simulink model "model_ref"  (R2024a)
settings: Solver=ode4  StartTime=0.0  StopTime=10  FixedStep=0.0001  RelTol=1e-3
model workspace (MAT data in the model file):
  Brake_MC_D = 3.3
  CarSimTCKMAP = [0.006425 0.006425 0.006425 0.006425 0.006424 0.006419 0.006386 0.006243 0.005735 0.004185 0.002578 0.000614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]
  CarSimTCLambdaPMAP = [1.864 1.78 1.701 1.608 1.56 1.519 1.464 1.412 1.356 1.309 1.259 1.203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]
  CarSimTCiMAP1 = [0 0.1 0.2 0.3 0.4 0.5 0.6 0.7 0.8 0.9 0.95 0.99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]
  CarSimTCiMAP2 = [0 0.102 0.202 0.306 0.353 0.4 0.452 0.502 0.551 0.6 0.65 0.7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]
  DOWN_Data_lookup = [0 0 0 0 0 0 0 0 0 0 0 0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]
  DOWN_Gear_lookup = [1 2 3 4 5]
  DOWN_Throttle_lookup = [0 1 2 3 4 5 6 7 8 9 10 11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]
  Diff_gear_ratio = 4.1
  MC_lever_ratio = 0.02381
  UP_Data_lookup = [13.2140963951 13.2140963951 13.2140963951 13.2140963951 13.2140963951 13.2140963951 13.6741047457 14.0455395451 14.3574336302 14.6810803701 15.0507893957 16.3806466373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]
  UP_Gear_lookup = [1 2 3 4 5]
  UP_Throttle_lookup = [0 1 2 3 4 5 6 7 8 9 10 11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]
  eng_One_Order_T = 0.005
  eng_T = [0 0 0 0 0 0 0 0 0 0 15 64.064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]
  eng_Ted = 0.005
  eng_n = [0 86.6667 173.333 433.333 750 866.667 1300 1733.33 2166.67 2600 3033.33 3466.67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]
  eng_throttle = [0 0.1 0.15 0.2 0.35 0.5 0.7 0.85 0.95 1]
  rotational_inertia_of_crankshaft = 0.16
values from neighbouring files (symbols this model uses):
  v0 = 0    [init.m]    (also in tempScript.m = 3)
  x0 = -27.92254    [init.m]    (also in tempScript.m = 66.5)
  y0 = 292.5054    [init.m]    (also in tempScript.m = 257.9)
  yaw = 0    [init.m]    (also in tempScript.m = -1.125)
undefined symbols (not defined in the file or in its folder): a_brake, a_thr, brake_table, thr_table
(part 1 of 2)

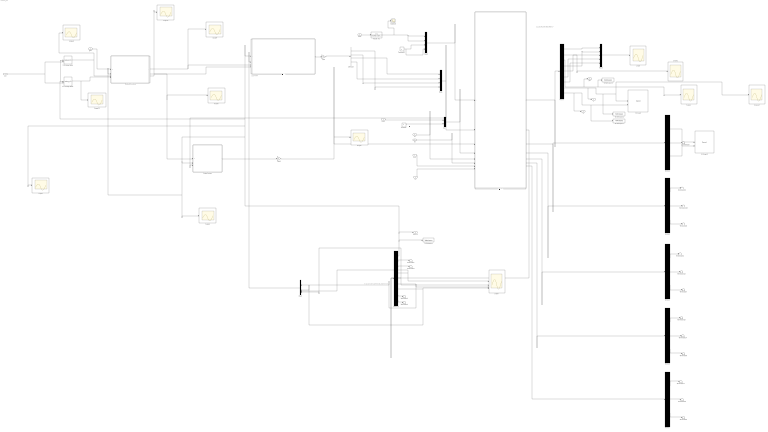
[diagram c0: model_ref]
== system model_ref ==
  note: 前轮
  note: 路肩
  note: x y phi AFL AFR ARL ARR X Y
  note: 档位 D N R P
  note: dx dy dphi dAFL dAFR dARL dARR dX dY
  note: 后轮
  note: 坡度
  acc : Inport  OutDataTypeStr=double  PortDimensions=1
  gear : Inport  Port=2  OutDataTypeStr=double  PortDimensions=1
  steer : Inport  Port=3  OutDataTypeStr=double  PortDimensions=1
  slope : Inport  Port=4  OutDataTypeStr=double  PortDimensions=1
  x0 : Inport  Port=5  OutDataTypeStr=double  PortDimensions=1
  y0 : Inport  Port=6  OutDataTypeStr=double  PortDimensions=1
  yaw : Inport  Port=7  OutDataTypeStr=double  PortDimensions=1
  v0 : Inport  Port=8  OutDataTypeStr=double  PortDimensions=1
  2-D Lookup Table : Lookup_n-D  BreakpointsForDimension1=0:0.1:12  BreakpointsForDimension2=a_thr  Table=thr_table  InternalRulePriority=Speed  RndMeth=Simplest
  2-D Lookup Table1 : Lookup_n-D  BreakpointsForDimension1=0:0.1:12  BreakpointsForDimension2=a_brake  Table=brake_table  InternalRulePriority=Speed  RndMeth=Simplest
  Brake System : Subsystem
  Constant : Constant  Value=0
  Constant11 : Constant  Value=0
  Demux : Demux  Outputs=[1 1 1 1 1 1 1 1 1]
  Demux1 : Demux  Outputs=[1 1 1 1 1 1 1 1 1]
  Demux2 : Demux  Outputs=[1 1 1 1]
  Demux{3..7} (5 alike) : Demux  Outputs=[1 1 1]
  Gain : Gain  Gain=1/5
  Gain1 : Gain
  MATLAB Function1 : MATLAB Function  TreatAsAtomicUnit=on
  Mux : Mux  Inputs=[1 1]
  Mux1 : Mux  Inputs=[1 1 1 1]
  Mux3 : Mux  Inputs=[1 1 1 1]
  Mux4 : Mux  Inputs=5
  Mux5 : Mux
  Scope{,1..6,8..13} (13 alike) : Scope
  Scope7 : Scope  NumInputPorts=4
  Terminator{1..17} (17 alike) : Terminator
  To Workspace : ToWorkspace  VariableName=velocity1  SaveFormat=Timeseries  SampleTime=-1
  To Workspace1 : ToWorkspace  VariableName=phi1  SaveFormat=Timeseries  SampleTime=-1
  To Workspace2 : ToWorkspace  VariableName=x1  SaveFormat=Timeseries  SampleTime=-1
  To Workspace3 : ToWorkspace  VariableName=y1  SaveFormat=Timeseries  SampleTime=-1
  Transfer Fcn : TransferFcn  Denominator=[0.0001 0.01414 1]
  XY Graph : Record  FileSettingsInternal="{\"entries\":[{\"content\":{\"excelSettings\":{\"content\":{},\"type\":\"Streamout.ExcelSettings\"}},\"type\":\"Streamout.FileSettingStorage\",\"uuid\":\"\"}],\"packageUris\":[\"http:\\/\\/schema.mathworks.com\\/mf0\\/streamout_blocks\\/R2020a\"],\"version\":\"1.0\"}"  Layout=[1 1]  SignalsInternal="{\"entries\":[{\"content\":{\"signals\":[{\"content\":{\"blockPath\":[],\"dimensions\":[1],\"domain\":\"\",\"lineColor\":\"#a2142f\",\"plots\":[ 1 ],\"port\":1,\"signalID\":1,\"signalName\":\"Demux:8\"},\"type\":\"RecordBlkView.Signal\",\"uuid\":\"\"},{\"content\":{\"blockPath\":[],\"dimensions\":[1],\"domain\":\"\",\"lineColor\":\"#139fff\",\"plots\":[ 1 ],\"port\":2,\"signalID\":2,\"signalName\":\"Demux:9\"},\"type\":\"RecordBlkView.Signal\",\"uuid\":\"\"}]},\"type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"  VisualizationBindings="{\"xyplotplugin\":{\"info\":[{\"series\":[{\"bindingParametersList\":[{\"parameter\":\"X-Axis\",\"signalID\":1,\"signalName\":\"Demux:8\"},{\"parameter\":\"Y-Axis\",\"signalID\":2,\"signalName\":\"Demux:9\"}],\"seriesID\":0}],\"subplotID\":1}]}}"  CompatibilityTag=XY  st=-1
  XY Graph1 : Record  FileSettingsInternal="{\"entries\":[{\"content\":{\"excelSettings\":{\"content\":{},\"type\":\"Streamout.ExcelSettings\"}},\"type\":\"Streamout.FileSettingStorage\",\"uuid\":\"\"}],\"packageUris\":[\"http:\\/\\/schema.mathworks.com\\/mf0\\/streamout_blocks\\/R2020a\"],\"version\":\"1.0\"}"  Layout=[1 1]  SignalsInternal="{\"entries\":[{\"content\":{\"signals\":[{\"content\":{\"blockPath\":[],\"dimensions\":[1],\"domain\":\"\",\"lineColor\":\"#a2142f\",\"plots\":[ 1 ],\"port\":1,\"signalID\":1,\"signalName\":\"Demux3:1\"},\"type\":\"RecordBlkView.Signal\",\"uuid\":\"\"},{\"content\":{\"blockPath\":[],\"dimensions\":[1],\"domain\":\"\",\"lineColor\":\"#139fff\",\"plots\":[ 1 ],\"port\":2,\"signalID\":2,\"signalName\":\"Demux3:3\"},\"type\":\"RecordBlkView.Signal\",\"uuid\":\"\"}]},\"ty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"  VisualizationBindings="{\"xyplotplugin\":{\"info\":[{\"series\":[{\"bindingParametersList\":[{\"parameter\":\"X-Axis\",\"signalID\":1,\"signalName\":\"Demux3:1\"},{\"parameter\":\"Y-Axis\",\"signalID\":2,\"signalName\":\"Demux3:3\"}],\"seriesID\":0}],\"subplotID\":1}]}}"  CompatibilityTag=XY  st=-1
  车辆动力学模型 : Subsystem
  驱动系统 : Subsystem
  x : Outport  OutDataTypeStr=double  PortDimensions=1  SampleTime=0
  y : Outport  Port=2  OutDataTypeStr=double  PortDimensions=1  SampleTime=0
  phi : Outport  Port=3  OutDataTypeStr=double  PortDimensions=1  SampleTime=0
  velocity : Outport  Port=4  OutDataTypeStr=double  PortDimensions=1  SampleTime=0
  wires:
  Demux2/2 -> Mux1/3
  车辆动力学模型/1(车辆位移状态) -> Demux/1
  Demux/6 -> Mux4/4
  Constant11/1 -> Mux3/4, Mux3/3
  Constant/1 -> Mux/2
  车辆动力学模型/2(车辆速度状态) -> Demux1/1
  acc/1 -> 2-D Lookup Table1/2, 2-D Lookup Table/2
  Demux1/3 -> Terminator2/1
  Demux1/2 -> Terminator1/1
  Demux6/2 -> Terminator14/1
  Mux5/1 -> 驱动系统/2(" 车轮角速度")
  MATLAB Function1/1(Dr_C) -> Scope4/1, 驱动系统/3(" 节气门开度")
  Demux7/1 -> Terminator17/1
  slope/1 -> Mux/1
  Demux6/1 -> Terminator15/1
  Mux3/1 -> 车辆动力学模型/1(Steering)
  MATLAB Function1/2(Br_C) -> Brake System/1(BrkPdlCmd), Scope5/1
  Demux/1 -> Mux4/1
  车辆动力学模型/4(全局坐标系_FL) -> Demux4/1
  Demux6/3 -> Terminator8/1
  steer/1 -> Transfer Fcn/1
  Demux1/6 -> Mux5/1, Scope7/3
  Demux7/2 -> Terminator16/1
  Demux/4 -> Mux4/2
  Brake System/1(BrkTrq) -> Gain1/1
  Demux3/3 -> XY Graph1/2
  车辆动力学模型/3(全局坐标系_质心) -> Demux3/1
  Demux2/1 -> Mux1/4
  Demux5/2 -> Terminator12/1
  Demux2/3 -> Mux1/1
  2-D Lookup Table1/1 -> Scope13/1, MATLAB Function1/4(bra)
  Demux7/3 -> Terminator9/1
  Demux/5 -> Mux4/3
  车辆动力学模型/7(全局坐标系_RR) -> Demux7/1
  Demux4/1 -> Terminator11/1
  Demux1/9 -> Terminator4/1
  Mux4/1 -> Scope/1
  Demux1/1 -> velocity/1, MATLAB Function1/2(v_x), Scope9/1, Brake System/2(dx), Scope3/1, 驱动系统/1(Vel_x 车辆纵向速度), 2-D Lookup Table1/1, 2-D Lookup Table/1, To Workspace/1
  Demux3/1 -> XY Graph1/1
  Gain1/1 -> 车辆动力学模型/3(Tor_B), Scope6/1
  2-D Lookup Table/1 -> MATLAB Function1/3(thrs), Scope8/1
  Demux1/4 -> Mux5/3, Scope7/1
  Demux4/3 -> Terminator6/1
  Demux1/5 -> Mux5/4, Scope7/2
  Demux2/4 -> Mux1/2
  Gain/1 -> Demux2/1
  MATLAB Function1/3(gear) -> Scope11/1, 驱动系统/4(档_D_N_R_P)
  Demux1/8 -> Terminator3/1
  Demux5/1 -> Terminator13/1
  Demux/9 -> y/1, To Workspace3/1, XY Graph/2
  Demux5/3 -> Terminator7/1
  Demux/2 -> Scope1/1
  Mux1/1 -> 车辆动力学模型/2(Tor_D), Brake System/3(怠速力矩)
  驱动系统/1(" 车轮输入力矩") -> Gain/1
  车辆动力学模型/6(全局坐标系_RL) -> Demux6/1
  gear/1 -> MATLAB Function1/1("gear ")
  Transfer Fcn/1 -> Scope10/1, Mux3/2, Mux3/1
  Demux3/2 -> Terminator5/1
  Demux1/7 -> Mux5/2, Scope7/4
  Demux4/2 -> Terminator10/1
  车辆动力学模型/5(全局坐标系_FR) -> Demux5/1
  Demux/3 -> phi/1, To Workspace1/1, Scope2/1
  Demux/8 -> x/1, To Workspace2/1, Scope12/1, XY Graph/1
  Demux/7 -> Mux4/5
  Mux/1 -> 车辆动力学模型/4(road)
  x0/1 -> 车辆动力学模型/5(x0)
  y0/1 -> 车辆动力学模型/6(y0)
  yaw/1 -> 车辆动力学模型/7(yaw)
  v0/1 -> 车辆动力学模型/8(v0)

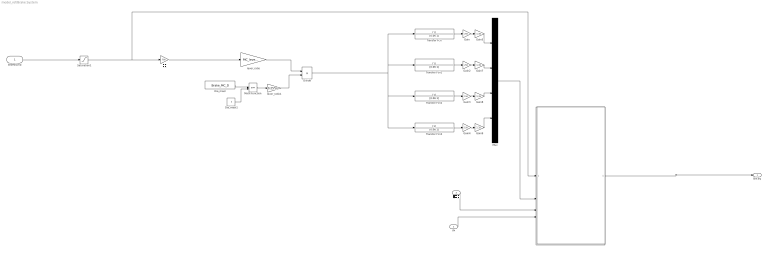
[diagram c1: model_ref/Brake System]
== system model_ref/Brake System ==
  BrkPdlCmd : Inport
  dx : Inport  Port=2
  怠速力矩 : Inport  Port=3
  Dia_mast : Constant  Value=Brake_MC_D
  Dia_mast1 : Constant  Value=2
  Divide : Product  Inputs=*/
  Gain : Gain  Gain=250
  Gain2 : Gain  Gain=250
  Gain3 : Gain  Gain=150
  Gain4 : Gain  Gain=150
  Gain{5,7..9} (4 alike) : Gain  Gain=1.35
  Math Function : Math  Operator=pow  SignedPower=on
  Mux : Mux  Inputs=[1 1 1 1]
  Saturation1 : Saturate  UpperLimit=1  LowerLimit=0
  Transfer Fcn{,1..3} (4 alike) : TransferFcn  Denominator=[0.06 1]
  lever_ratio : Gain  Gain=MC_lever_ratio
  lever_ratio1 : Gain  Gain=0.25*pi
  制动转矩 : MATLAB Function  TreatAsAtomicUnit=on
  行程 : Gain  Gain=700
  BrkTrq : Outport
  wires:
  Gain/1 -> Gain5/1
  Gain4/1 -> Gain9/1
  Gain2/1 -> Gain7/1
  Gain3/1 -> Gain8/1
  Transfer Fcn3/1 -> Gain4/1
  Transfer Fcn2/1 -> Gain3/1
  Transfer Fcn1/1 -> Gain2/1
  BrkPdlCmd/1 -> Saturation1/1
  Transfer Fcn/1 -> Gain/1
  Dia_mast1/1 -> Math Function/2
  lever_ratio1/1 -> Divide/2
  Dia_mast/1 -> Math Function/1
  Math Function/1 -> lever_ratio1/1
  lever_ratio/1 -> Divide/1
  Gain5/1 -> Mux/1
  Gain7/1 -> Mux/2
  Gain8/1 -> Mux/3
  Gain9/1 -> Mux/4
  行程/1 -> lever_ratio/1
  Divide/1 -> Transfer Fcn/1, Transfer Fcn1/1, Transfer Fcn3/1, Transfer Fcn2/1
  制动转矩/1(y) -> BrkTrq/1
  dx/1 -> 制动转矩/4(dx)
  Mux/1 -> 制动转矩/2(Tor_Br)
  怠速力矩/1 -> 制动转矩/3(Tor_Dr)
  Saturation1/1 -> 制动转矩/1(Br_Con), 行程/1

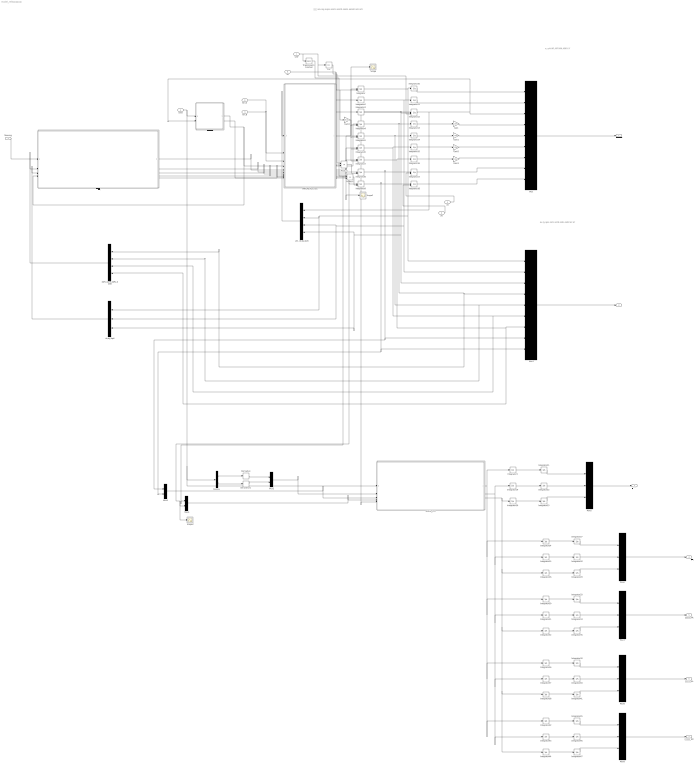
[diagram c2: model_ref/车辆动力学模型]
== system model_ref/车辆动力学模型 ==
  note: x y phi AFL AFR ARL ARR X Y
  note: dx dy dphi dAFL dAFR dARL dARR dX dY
  note: 输出： ddx ddy ddphi ddAFL ddAFR ddARL ddARR ddX ddY
  Steering : Inport
  Tor_D : Inport  Port=2
  Tor_B : Inport  Port=3
  road : Inport  Port=4
  x0 : Inport  Port=5
  y0 : Inport  Port=6
  yaw : Inport  Port=7
  v0 : Inport  Port=8
  Cos : Trigonometry  Operator=cos
  Demux : Demux  Outputs=[1 1]
  Derivative : Derivative
  Derivative1 : Derivative
  Gain{,1..3} (4 alike) : Gain  Gain=0.314
  Gain4 : Gain  Gain=1/0.314
  Global_XYZ : MATLAB Function  TreatAsAtomicUnit=on
  Integrator : Integrator  InitialConditionSource=external  InitialCondition=v0
  Integrator{1..3,10..11,13..16,19..47} (38 alike) : Integrator
  Integrator12 : Integrator  InitialConditionSource=external  InitialCondition=yaw
  Integrator17 : Integrator  InitialConditionSource=external  InitialCondition=x0
  Integrator18 : Integrator  InitialConditionSource=external  InitialCondition=y0
  Integrator{4..7} (4 alike) : Integrator  InitialConditionSource=external  InitialCondition=v0/0.314
  Integrator8 : Integrator  InitialConditionSource=external  InitialCondition=v0*cos(yaw)
  Integrator9 : Integrator  InitialConditionSource=external  InitialCondition=v0*sin(yaw)
  MATLAB Function : MATLAB Function  TreatAsAtomicUnit=on
  Mux : Mux  Inputs=[1 1 1 1 1 1 1 1 1]
  Mux1 : Mux  Inputs=[1 1 1 1 1 1 1 1 1]
  Mux2 : Mux  Inputs=[1 1]
  Mux3 : Mux  Inputs=[1 1]
  Mux4 : Mux  Inputs=[1 1]
  Mux{5..9} (5 alike) : Mux  Inputs=[1 1 1]
  Product : Product
  Product1 : Product
  Scope : Scope
  Scope1 : Scope
  Scope2 : Scope
  Trigonometric Function : Trigonometry
  dAFL,dAFR,dARL,dARR : Mux  Inputs=[1 1 1 1]
  dx,dy,dphi : Mux  Inputs=[1 1 1]
  "phi, dx,dy,dphi" : Mux  Inputs=[1 1 1 1]
  车轮系统 : Subsystem
  轮胎垂直载荷 : Subsystem
  车辆位移状态 : Outport
  车辆速度状态 : Outport  Port=2
  全局坐标系_质心 : Outport  Port=3
  全局坐标系_FL : Outport  Port=4
  全局坐标系_FR : Outport  Port=5
  全局坐标系_RL : Outport  Port=6
  全局坐标系_RR : Outport  Port=7
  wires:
  Product/1 -> Integrator8/2
  Global_XYZ/1(ddX_G) -> Integrator24/1, Integrator30/1, Integrator36/1, Integrator42/1, Integrator1/1
  yaw/1 -> Trigonometric Function/1, Cos/1, Integrator12/2
  Integrator40/1 -> Mux8/2
  Gain3/1 -> Mux/7
  Mux1/1 -> 车辆速度状态/1
  Integrator47/1 -> Mux9/3
  Integrator38/1 -> Integrator41/1
  轮胎垂直载荷/2(w_cg) -> MATLAB Function/10(w_cg)
  road/1 -> 轮胎垂直载荷/1(road), Global_XYZ/1(road), Demux/1
  Integrator46/1 -> Mux9/2
  Gain1/1 -> Mux/5
  Integrator14/1 -> Gain1/1
  Mux4/1 -> Global_XYZ/4(ddu)
  Trigonometric Function/1 -> Product1/1
  Integrator16/1 -> Gain3/1
  车轮系统/3(左后轮胎力) -> MATLAB Function/7(FwRL)
  MATLAB Function/8(ddX) -> Scope1/1, Integrator8/1, Mux4/1
  Integrator26/1 -> Integrator29/1
  MATLAB Function/5(ddAFR) -> Integrator5/1
  Integrator24/1 -> Integrator27/1
  Product1/1 -> Integrator9/2
  Integrator11/1 -> Mux/2
  Integrator19/1 -> Integrator22/1
  Integrator32/1 -> Integrator35/1
  y0/1 -> Integrator18/2
  v0/1 -> Product1/2, Product/2, Gain4/1, Integrator/2
  Mux9/1 -> 全局坐标系_RR/1
  Derivative/1 -> Mux2/1
  Integrator29/1 -> Mux6/3
  "phi, dx,dy,dphi"/1 -> MATLAB Function/1(u)
  Integrator7/1 -> Integrator16/1, Mux1/7, dAFL,dAFR,dARL,dARR/4
  Mux6/1 -> 全局坐标系_FL/1
  Integrator2/1 -> Integrator11/1, Mux1/2, "phi, dx,dy,dphi"/3, dx,dy,dphi/2
  dx,dy,dphi/1 -> 车轮系统/3(纵向速度 横向速度 横摆角速度)
  Integrator25/1 -> Integrator28/1
  Integrator27/1 -> Mux6/1
  Cos/1 -> Product/1
  车轮系统/2(右前轮胎力) -> MATLAB Function/6(FwFR)
  Integrator/1 -> Integrator10/1, Mux1/1, "phi, dx,dy,dphi"/2, dx,dy,dphi/1
  Integrator15/1 -> Gain2/1
  车轮系统/5(四轮转向角) -> MATLAB Function/9(Steering)
  Integrator1/1 -> Integrator21/1
  MATLAB Function/6(ddARL) -> Integrator6/1
  Tor_D/1 -> MATLAB Function/2(Tor_D)
  Gain2/1 -> Mux/6
  Integrator45/1 -> Mux9/1
  轮胎垂直载荷/1(Fz) -> MATLAB Function/4(Fz), 车轮系统/4(轮胎垂直载荷)
  Integrator20/1 -> Integrator23/1
  车轮系统/1(左前轮胎力) -> MATLAB Function/5(FwFL)
  Integrator6/1 -> Integrator15/1, Mux1/6, dAFL,dAFR,dARL,dARR/3
  Integrator33/1 -> Mux7/1
  Integrator31/1 -> Integrator34/1
  x0/1 -> Integrator17/2
  Integrator44/1 -> Integrator47/1
  Integrator3/1 -> Integrator12/1, Mux1/3, "phi, dx,dy,dphi"/4, dx,dy,dphi/3
  Mux5/1 -> 全局坐标系_质心/1
  Integrator42/1 -> Integrator45/1
  Mux8/1 -> 全局坐标系_RL/1
  Mux2/1 -> Global_XYZ/2(droad)
  Integrator21/1 -> Mux5/1
  Integrator18/1 -> Mux/9
  Integrator43/1 -> Integrator46/1
  MATLAB Function/9(ddY) -> Mux4/2, Scope2/1, Integrator9/1
  Integrator9/1 -> Integrator18/1, Mux3/2, Mux1/9
  Integrator13/1 -> Gain/1
  Integrator28/1 -> Mux6/2
  车轮系统/4(右后轮胎力) -> MATLAB Function/8(FwRR)
  Integrator35/1 -> Mux7/3
  MATLAB Function/2(ddy) -> Integrator2/1
  MATLAB Function/3(ddphi) -> Integrator3/1
  Mux3/1 -> Global_XYZ/3(du)
  Derivative1/1 -> Mux2/2
  Demux/2 -> Derivative1/1
  Integrator4/1 -> Integrator13/1, Mux1/4, dAFL,dAFR,dARL,dARR/1
  Integrator23/1 -> Mux5/3
  Global_XYZ/3(ddZ_G) -> Integrator26/1, Integrator32/1, Integrator38/1, Integrator44/1, Integrator20/1
  Integrator22/1 -> Mux5/2
  MATLAB Function/1(ddx) -> Scope/1, Integrator/1
  Integrator5/1 -> Integrator14/1, dAFL,dAFR,dARL,dARR/2, Mux1/5
  Integrator36/1 -> Integrator39/1
  Gain/1 -> Mux/4
  Tor_B/1 -> MATLAB Function/3(Tor_B)
  Global_XYZ/2(ddY_G) -> Integrator25/1, Integrator31/1, Integrator37/1, Integrator43/1, Integrator19/1
  Integrator17/1 -> Mux/8
  Mux7/1 -> 全局坐标系_FR/1
  Steering/1 -> 车轮系统/1(转向角)
  Integrator37/1 -> Integrator40/1
  MATLAB Function/4(ddAFL) -> Integrator4/1
  Gain4/1 -> Integrator7/2, Integrator6/2, Integrator5/2, Integrator4/2
  Integrator8/1 -> Integrator17/1, Mux3/1, Mux1/8
  Integrator41/1 -> Mux8/3
  Integrator12/1 -> Global_XYZ/5(phi), "phi, dx,dy,dphi"/1, Mux/3, 轮胎垂直载荷/2(横摆角)
  Integrator30/1 -> Integrator33/1
  dAFL,dAFR,dARL,dARR/1 -> 车轮系统/2(轮胎角速度)
  Integrator10/1 -> Mux/1
  Integrator39/1 -> Mux8/1
  Demux/1 -> Derivative/1
  Integrator34/1 -> Mux7/2
  MATLAB Function/7(ddARR) -> Integrator7/1
  Mux/1 -> 车辆位移状态/1

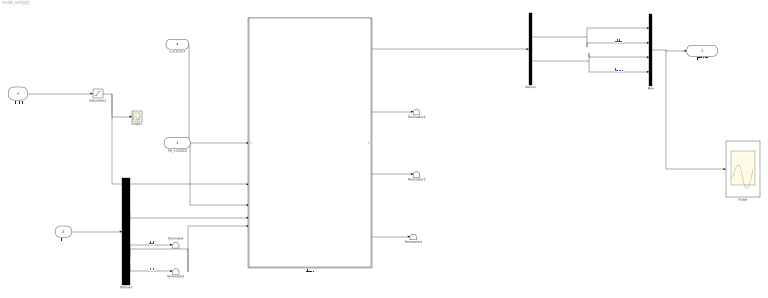
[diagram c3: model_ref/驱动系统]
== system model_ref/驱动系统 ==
  Vel_x 车辆纵向速度 : Inport
  " 车轮角速度" : Inport  Port=2
  " 节气门开度" : Inport  Port=3
  档_D_N_R_P : Inport  Port=4
  Demux : Demux  Outputs=2
  Demux1 : Demux
  Mux : Mux  Inputs=[1 1 1 1]
  Saturation1 : Saturate  UpperLimit=1  LowerLimit=0
  Scope : Scope
  Scope1 : Scope
  Terminator{,1..4} (5 alike) : Terminator
  发动机模型 : Subsystem
  " 车轮输入力矩" : Outport
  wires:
  " 节气门开度"/1 -> Saturation1/1
  发动机模型/3(Gear) -> Terminator3/1
  Vel_x 车辆纵向速度/1 -> 发动机模型/3(Vel_x 车辆纵向速度)
  发动机模型/4(TCRatio) -> Terminator4/1
  发动机模型/2(EngSpd) -> Terminator2/1
  Saturation1/1 -> Scope1/1, 发动机模型/2(节气门开度)
  发动机模型/1(WhlTrq) -> Demux/1
  档_D_N_R_P/1 -> 发动机模型/1(GearCmd)
  Mux/1 -> Scope/1, " 车轮输入力矩"/1
  Demux/2 -> Mux/4, Mux/3  "从动轮力矩"
  Demux/1 -> Mux/2, Mux/1  "驱动轮力矩"
  Demux1/1 -> 发动机模型/4(驱动轮_L)
  Demux1/2 -> 发动机模型/5(驱动轮_R)
  Demux1/4 -> Terminator1/1  "从动轮"
  Demux1/3 -> Terminator/1  "从动轮"
  " 车轮角速度"/1 -> Demux1/1

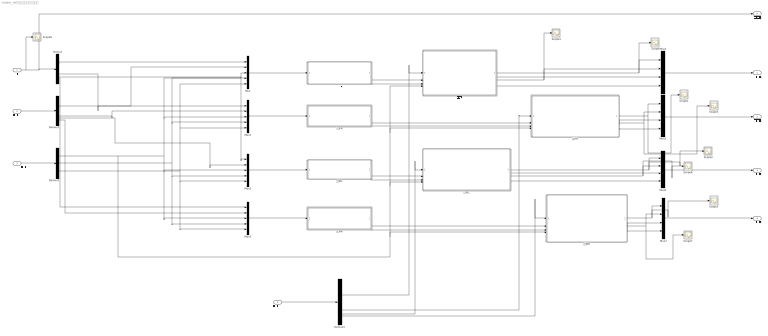
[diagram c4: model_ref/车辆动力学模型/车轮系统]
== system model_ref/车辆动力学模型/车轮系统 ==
  转向角 : Inport
  轮胎角速度 : Inport  Port=2
  纵向速度 横向速度 横摆角速度 : Inport  Port=3
  轮胎垂直载荷 : Inport  Port=4
  Demux : Demux
  Demux1 : Demux
  Demux2 : Demux  Outputs=3
  Demux3 : Demux
  Mux{,1..3} (4 alike) : Mux  Inputs=[1 1 1 1 1]
  Mux{4..7} (4 alike) : Mux  Inputs=[1 1 1 1]
  Scope{,1..8} (9 alike) : Scope
  车轮FL : MATLAB Function  TreatAsAtomicUnit=on
  车轮FR : MATLAB Function  TreatAsAtomicUnit=on
  车轮RL : MATLAB Function  TreatAsAtomicUnit=on
  车轮RR : MATLAB Function  TreatAsAtomicUnit=on
  轮胎FL : MATLAB Function  TreatAsAtomicUnit=on
  轮胎FR : MATLAB Function  TreatAsAtomicUnit=on
  轮胎RL : MATLAB Function  TreatAsAtomicUnit=on
  轮胎RR : MATLAB Function  TreatAsAtomicUnit=on
  左前轮胎力 : Outport
  右前轮胎力 : Outport  Port=2
  左后轮胎力 : Outport  Port=3
  右后轮胎力 : Outport  Port=4
  四轮转向角 : Outport  Port=5
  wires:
  Mux7/1 -> 右后轮胎力/1
  Demux2/1 -> Mux1/3, Mux/3, Mux3/3, Mux2/3, 轮胎RR/4(VS), 轮胎FR/4(VS), 轮胎FL/4(VS), 轮胎RL/4(VS)
  Mux6/1 -> 左后轮胎力/1
  Mux5/1 -> 右前轮胎力/1
  Mux4/1 -> 左前轮胎力/1
  轮胎FL/3(MZ0) -> Mux4/3
  轮胎RR/4(MY) -> Mux7/4
  轮胎RR/3(MZ0) -> Mux7/3
  轮胎RR/2(FY0) -> Mux7/2, Scope7/1
  轮胎RR/1(FX0) -> Mux7/1, Scope3/1
  轮胎RL/4(MY) -> Mux6/4
  轮胎RL/3(MZ0) -> Mux6/3
  轮胎RL/2(FY0) -> Mux6/2, Scope6/1
  轮胎RL/1(FX0) -> Mux6/1, Scope2/1
  轮胎FR/4(MY) -> Mux5/4
  轮胎FR/3(MZ0) -> Mux5/3
  轮胎FR/2(FY0) -> Mux5/2, Scope5/1
  轮胎FR/1(FX0) -> Mux5/1, Scope1/1
  轮胎FL/4(MY) -> Mux4/4
  轮胎FL/2(FY0) -> Scope4/1, Mux4/2
  轮胎FL/1(FX0) -> Mux4/1, Scope/1
  Demux3/1 -> 轮胎FL/1(FZ)
  Demux3/2 -> 轮胎FR/1(FZ)
  Demux3/3 -> 轮胎RL/1(FZ)
  Demux3/4 -> 轮胎RR/1(FZ)
  轮胎垂直载荷/1 -> Demux3/1
  车轮RR/1(sigma_x) -> 轮胎RR/2(KAPPA)
  车轮RR/2(alpha) -> 轮胎RR/3(ALPHA)
  车轮RL/2(alpha) -> 轮胎RL/3(ALPHA)
  车轮RL/1(sigma_x) -> 轮胎RL/2(KAPPA)
  车轮FR/1(sigma_x) -> 轮胎FR/2(KAPPA)
  车轮FR/2(alpha) -> 轮胎FR/3(ALPHA)
  车轮FL/2(alpha) -> 轮胎FL/3(ALPHA)
  车轮FL/1(sigma_x) -> 轮胎FL/2(KAPPA)
  Mux1/1 -> 车轮FR/1(u)
  Demux2/3 -> Mux1/5, Mux/5, Mux3/5, Mux2/5
  Demux2/2 -> Mux1/4, Mux/4, Mux3/4, Mux2/4
  Demux1/4 -> Mux3/2
  Demux1/3 -> Mux2/2
  Demux1/2 -> Mux1/2
  Demux1/1 -> Mux/2
  纵向速度 横向速度 横摆角速度/1 -> Demux2/1
  轮胎角速度/1 -> Demux1/1
  Demux/4 -> Mux3/1
  Demux/3 -> Mux2/1
  Demux/2 -> Mux1/1
  Demux/1 -> Mux/1
  转向角/1 -> Scope8/1, Demux/1, 四轮转向角/1
  Mux3/1 -> 车轮RR/1(u)
  Mux2/1 -> 车轮RL/1(u)
  Mux/1 -> 车轮FL/1(u)

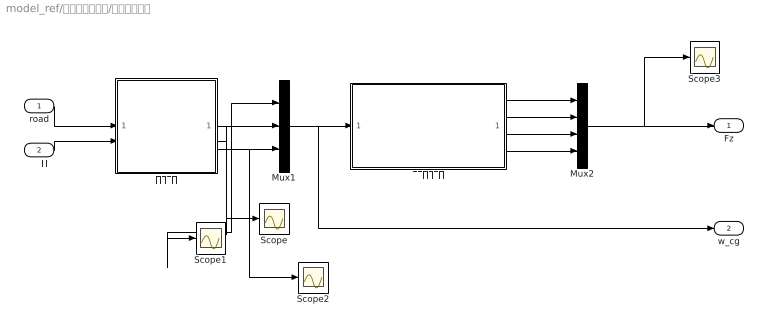
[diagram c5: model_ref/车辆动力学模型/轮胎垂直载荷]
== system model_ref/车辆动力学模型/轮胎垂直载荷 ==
  road : Inport
  横摆角 : Inport  Port=2
  Mux1 : Mux  Inputs=[1 1 1]
  Mux2 : Mux  Inputs=[1 1 1 1]
  Scope{,1..3} (4 alike) : Scope
  车辆重力 : MATLAB Function  TreatAsAtomicUnit=on
  轮胎垂直载荷 : MATLAB Function  TreatAsAtomicUnit=on
  Fz : Outport
  w_cg : Outport  Port=2
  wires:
  横摆角/1 -> 车辆重力/2(phi)
  车辆重力/1(G_x) -> Mux1/1, Scope1/1
  车辆重力/3(G_z) -> Mux1/3, Scope2/1
  Mux1/1 -> 轮胎垂直载荷/1(u), w_cg/1
  轮胎垂直载荷/2(Fz_FR) -> Mux2/2
  Mux2/1 -> Fz/1, Scope3/1
  轮胎垂直载荷/1(Fz_FL) -> Mux2/1
  轮胎垂直载荷/3(Fz_RL) -> Mux2/3
  轮胎垂直载荷/4(Fz_RR) -> Mux2/4
  车辆重力/2(G_y) -> Mux1/2, Scope/1
  road/1 -> 车辆重力/1(u)

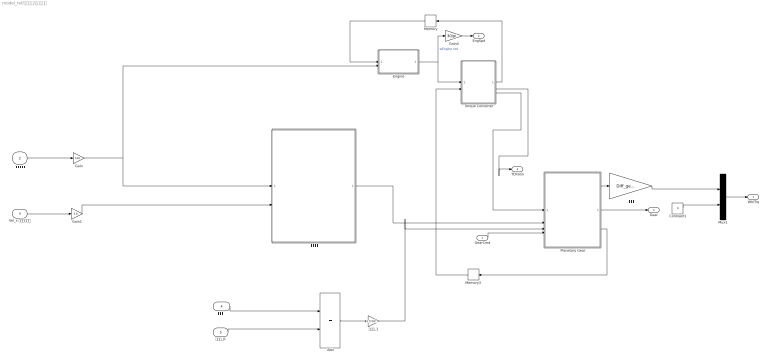
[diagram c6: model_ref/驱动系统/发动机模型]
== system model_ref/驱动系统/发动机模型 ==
  GearCmd : Inport
  节气门开度 : Inport  Port=2
  Vel_x 车辆纵向速度 : Inport  Port=3
  驱动轮_L : Inport  Port=4
  驱动轮_R : Inport  Port=5
  Add : Sum
  Constant1 : Constant  Value=0
  Engine : Subsystem
  Gain : Gain  Gain=100
  Gain1 : Gain  Gain=3.6
  Gain4 : Gain  Gain=30/pi
  Memory : Memory
  Memory3 : Memory
  Mux1 : Mux  Inputs=2
  Planetary Gear : Subsystem
  Torque Converter : Subsystem
  主减速 : Gain  Gain=Diff_gear_ratio/2
  主减速_1 : Gain  Gain=0.5*Diff_gear_ratio
  升降档位 : Subsystem
  WhlTrq : Outport
  EngSpd : Outport  Port=2
  Gear : Outport  Port=3
  TCRatio : Outport  Port=4
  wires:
  Planetary Gear/2(GearOut) -> Gear/1
  升降档位/1(档位) -> Planetary Gear/2(Gear)
  Gain1/1 -> 升降档位/2(Vel_x 车辆纵向速度)
  GearCmd/1 -> Planetary Gear/4(GearCmd)
  Torque Converter/2(TCi) -> TCRatio/1
  Memory3/1 -> Torque Converter/2(wt)
  Gain/1 -> Engine/2(Throttle), 升降档位/1(节气门开度)
  节气门开度/1 -> Gain/1
  Torque Converter/1(Tp) -> Memory/1
  主减速_1/1 -> Planetary Gear/3(whlSpd)
  Gain4/1 -> EngSpd/1
  Planetary Gear/1(To) -> 主减速/1
  Planetary Gear/3(TurboSpd) -> Memory3/1
  Engine/1(发动机输出角速度) -> Gain4/1, Torque Converter/1(we=wp)  "wEngine rad"
  驱动轮_L/1 -> Add/1
  Add/1 -> 主减速_1/1
  Torque Converter/3(Tt) -> Planetary Gear/1(Tt)
  Memory/1 -> Engine/1(Tp)
  Vel_x 车辆纵向速度/1 -> Gain1/1
  驱动轮_R/1 -> Add/2
  Mux1/1 -> WhlTrq/1
  主减速/1 -> Mux1/1
  Constant1/1 -> Mux1/2

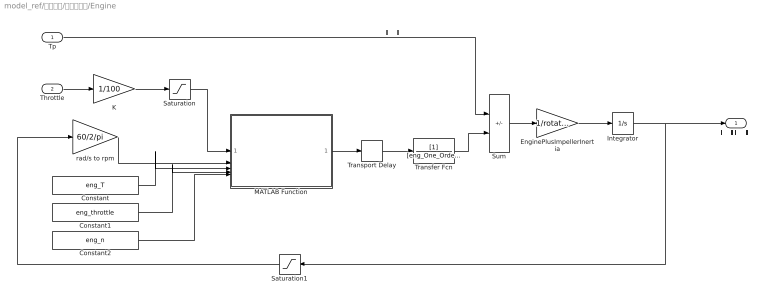
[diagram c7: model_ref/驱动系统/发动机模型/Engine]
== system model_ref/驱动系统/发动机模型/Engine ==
  note: 泵轮输入力矩
  Tp : Inport
  Throttle : Inport  Port=2
  Constant : Constant  Value=eng_T
  Constant1 : Constant  Value=eng_throttle
  Constant2 : Constant  Value=eng_n
  EnginePlusImpellerInertia : Gain  Gain=1/rotational_inertia_of_crankshaft  SaturateOnIntegerOverflow=on
  Integrator : Integrator  InitialCondition=750*2*pi/60  LimitOutput=on  UpperSaturationLimit=6500*2*pi/60  LowerSaturationLimit=750*2*pi/60  ZeroCross=off
  K : Gain  Gain=1/100  SaturateOnIntegerOverflow=on
  MATLAB Function : MATLAB Function  TreatAsAtomicUnit=on
  Saturation : Saturate  UpperLimit=1  LowerLimit=0.0
  Saturation1 : Saturate  UpperLimit=6500  LowerLimit=0
  Sum : Sum  Inputs=-+  InputSameDT=on  SaturateOnIntegerOverflow=on
  Transfer Fcn : TransferFcn  Denominator=[eng_One_Order_T 1]
  Transport Delay : TransportDelay  DelayTime=eng_Ted
  rad/s to rpm : Gain  Gain=60/2/pi
  发动机输出角速度 : Outport
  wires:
  Integrator/1 -> 发动机输出角速度/1, Saturation1/1
  Constant1/1 -> MATLAB Function/4(Row)
  Constant/1 -> MATLAB Function/3(TbVal)
  Constant2/1 -> MATLAB Function/5(Col)
  Tp/1 -> Sum/1
  Saturation1/1 -> rad/s to rpm/1
  K/1 -> Saturation/1
  Throttle/1 -> K/1
  MATLAB Function/1(y) -> Transport Delay/1
  rad/s to rpm/1 -> MATLAB Function/2(u2)
  Saturation/1 -> MATLAB Function/1(u1)
  Transfer Fcn/1 -> Sum/2
  Transport Delay/1 -> Transfer Fcn/1
  EnginePlusImpellerInertia/1 -> Integrator/1
  Sum/1 -> EnginePlusImpellerInertia/1

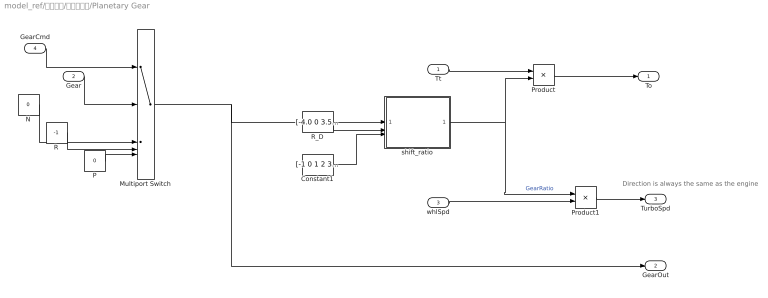
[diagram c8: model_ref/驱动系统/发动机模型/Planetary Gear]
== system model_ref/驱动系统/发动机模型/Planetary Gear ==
  note: Direction is always the same as the engine
  Tt : Inport
  Gear : Inport  Port=2
  whlSpd : Inport  Port=3
  GearCmd : Inport  Port=4
  Constant1 : Constant  Value=[-1 0 1 2 3 4 5]
  Multiport Switch : MultiPortSwitch  Inputs=4
  N : Constant  Value=0
  P : Constant  Value=0
  Product : Product  InputSameDT=on  SaturateOnIntegerOverflow=on
  Product1 : Product  InputSameDT=on  SaturateOnIntegerOverflow=on
  R : Constant  Value=-1
  R_D : Constant  Value=[-4.0 0 3.538 2.06 1.404 1 0.713]
  shift_ratio : MATLAB Function  TreatAsAtomicUnit=on
  To : Outport
  GearOut : Outport  Port=2
  TurboSpd : Outport  Port=3
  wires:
  P/1 -> Multiport Switch/5
  R/1 -> Multiport Switch/4
  N/1 -> Multiport Switch/3
  Product/1 -> To/1
  Multiport Switch/1 -> GearOut/1, shift_ratio/1(u)
  GearCmd/1 -> Multiport Switch/1
  whlSpd/1 -> Product1/2
  shift_ratio/1(ratio) -> Product/2, Product1/1  "GearRatio"
  R_D/1 -> shift_ratio/2(TbVal)
  Constant1/1 -> shift_ratio/3(Brkdots)
  Gear/1 -> Multiport Switch/2
  Tt/1 -> Product/1
  Product1/1 -> TurboSpd/1

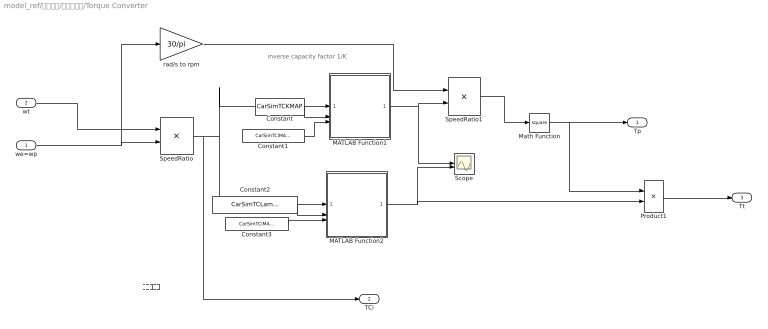
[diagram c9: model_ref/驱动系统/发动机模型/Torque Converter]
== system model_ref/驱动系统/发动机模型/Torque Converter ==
  note: inverse capacity factor 1/K
  note: 扭矩比系数
  we=wp : Inport
  wt : Inport  Port=2
  Constant : Constant  Value=CarSimTCKMAP
  Constant1 : Constant  Value=CarSimTCiMAP1
  Constant2 : Constant  Value=CarSimTCLambdaPMAP
  Constant3 : Constant  Value=CarSimTCiMAP2
  MATLAB Function1 : MATLAB Function  TreatAsAtomicUnit=on
  MATLAB Function2 : MATLAB Function  TreatAsAtomicUnit=on
  Math Function : Math  Operator=square  SignedPower=on
  Product1 : Product  RndMeth=Zero
  Scope : Scope  NumInputPorts=2
  SpeedRatio : Product  Inputs=*/  InputSameDT=on  SaturateOnIntegerOverflow=on
  SpeedRatio1 : Product  Inputs=**  InputSameDT=on  SaturateOnIntegerOverflow=on
  rad/s to rpm : Gain  Gain=30/pi
  Tp : Outport
  TCi : Outport  Port=2
  Tt : Outport  Port=3
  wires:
  MATLAB Function2/1(y) -> Scope/2, Product1/2
  SpeedRatio/1 -> TCi/1, MATLAB Function1/1(u), MATLAB Function2/1(u)
  Constant2/1 -> MATLAB Function2/2(TbVal)
  Constant3/1 -> MATLAB Function2/3(Brkdots)
  MATLAB Function1/1(y) -> SpeedRatio1/2, Scope/1
  Constant1/1 -> MATLAB Function1/3(Brkdots)
  Constant/1 -> MATLAB Function1/2(TbVal)
  rad/s to rpm/1 -> SpeedRatio1/1
  SpeedRatio1/1 -> Math Function/1
  Math Function/1 -> Product1/1, Tp/1
  Product1/1 -> Tt/1
  we=wp/1 -> SpeedRatio/2, rad/s to rpm/1
  wt/1 -> SpeedRatio/1

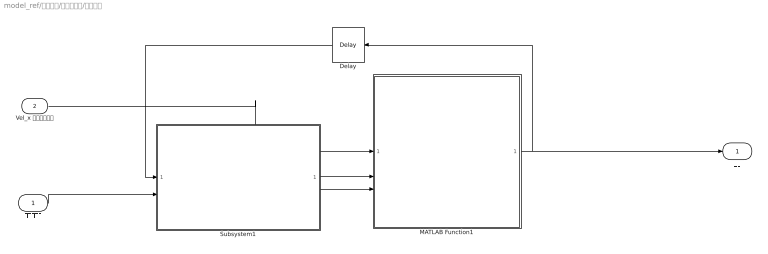
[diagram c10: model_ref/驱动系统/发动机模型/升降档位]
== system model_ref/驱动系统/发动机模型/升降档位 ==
  节气门开度 : Inport
  Vel_x 车辆纵向速度 : Inport  Port=2
  Delay : Delay  DelayLength=1  InitialCondition=0
  MATLAB Function1 : MATLAB Function  TreatAsAtomicUnit=on
  Subsystem1 : Subsystem
  档位 : Outport
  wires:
  Delay/1 -> Subsystem1/1(档位)
  节气门开度/1 -> Subsystem1/2(节气门开度)
  Subsystem1/2(down_th) -> MATLAB Function1/3(down_th)
  Subsystem1/1(up_th) -> MATLAB Function1/2(up_th)
  MATLAB Function1/1(Gear) -> 档位/1, Delay/1
  Vel_x 车辆纵向速度/1 -> MATLAB Function1/1(v)

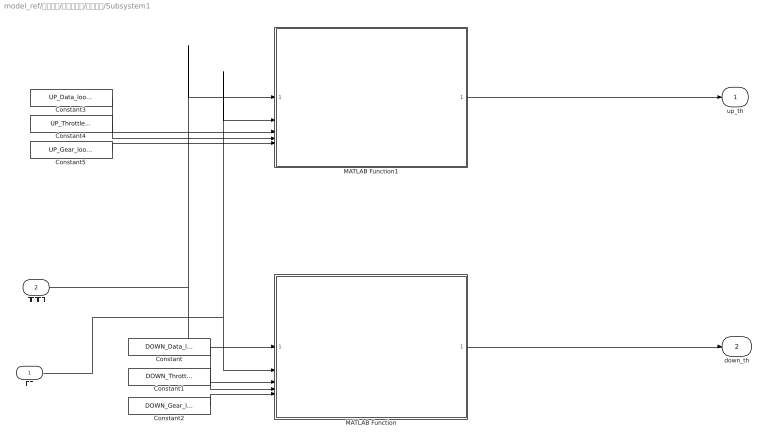
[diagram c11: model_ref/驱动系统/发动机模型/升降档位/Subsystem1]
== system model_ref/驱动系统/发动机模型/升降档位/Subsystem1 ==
  档位 : Inport
  节气门开度 : Inport  Port=2
  Constant : Constant  Value=DOWN_Data_lookup
  Constant1 : Constant  Value=DOWN_Throttle_lookup
  Constant2 : Constant  Value=DOWN_Gear_lookup
  Constant3 : Constant  Value=UP_Data_lookup
  Constant4 : Constant  Value=UP_Throttle_lookup
  Constant5 : Constant  Value=UP_Gear_lookup
  MATLAB Function : MATLAB Function  TreatAsAtomicUnit=on
  MATLAB Function1 : MATLAB Function  TreatAsAtomicUnit=on
  up_th : Outport  InitialOutput=0
  down_th : Outport  Port=2  InitialOutput=0
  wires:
  Constant4/1 -> MATLAB Function1/4(Row)
  Constant/1 -> MATLAB Function/3(TbVal)
  MATLAB Function1/1(y) -> up_th/1
  MATLAB Function/1(y) -> down_th/1
  档位/1 -> MATLAB Function/2(u2), MATLAB Function1/2(u2)
  Constant1/1 -> MATLAB Function/4(Row)
  Constant2/1 -> MATLAB Function/5(Col)
  Constant5/1 -> MATLAB Function1/5(Col)
  Constant3/1 -> MATLAB Function1/3(TbVal)
  节气门开度/1 -> MATLAB Function/1(u1), MATLAB Function1/1(u1)

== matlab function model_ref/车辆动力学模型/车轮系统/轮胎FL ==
function [FX0,FY0,MZ0,MY]=MagicTire(FZ,KAPPA,ALPHA,VS)
% The Magic tire model fcn

% INPUT 1 : VERTICAL LOAD FORCE --- FZ
% INPUT 2 : TIRE SIDESLIP ANGLE --- ALPHA
% INPUT 3 : TIRE LONGITUDINAL SLIP RATIO --- KAPPA
% INPUT 4 : TIRE CONTACT CENTER VELOCITY --- VS
% INPUT 5 : TIRE CAMBER ---GAMMA
GAMMA=0;
ALPHA=-ALPHA;           % 根据侧倾角定义
%% TIRE DATA
R0 = 0.344; % TIRE RADIUS (M)
Re = 0.314;   % EFFECTIVE RADIUS (M)
V0 = 16.6;  % REFERENCE VELOCITY 60 (KM/H)
FZ0 = 4850; % UNLOAD NOMINAL FORCE (N)

%% SCALIING FACTORS LAMDA
%* PURE SLIP
LFZ0 = 1; % NOMINAL LOAD
LMUX = 1; % PEAK FRICTION COEFFICENT LONGITUDINAL
LMUY = 1; % PEAK FRICTION COEFFICENT LATERAL
LMUV = 1; % SLIP DECAYING FRICTION
LKX = 1;  % BRAKE SLIP STIFFNESS
LKY = 1;  % CORNERING STIFFNESS
LCX = 1;  % SHAPE FACTOR
LCY = 1;  % SHAPE FACTOR
LEX = 1;  % CURVATURE FACTOR
LEY = 1;  % CURVATURE FACTOR
LHX = 0;  % HORIZONTAL FACTOR
LHY = 0;  % HORIZONTAL FACTOR
LVX = 0;  % VERTICAL FACTOR
LVY = 0;  % 
LGAY = 1; % CAMBER FORCE STIFFNESS
LGAZ = 0; % CAMBER TORQUE STIFFNESS
LT = 1;   % PNEUMATIC TRAIL
LMR = 0;  % RESIDUAL TORQUE (LRES IN EXCEL)

%* COMBINED SLIP
LXAL = 0; % ALPHA INFLUENCE ON Fx
LYKA = 0; % KAPPA INFLUENCE ON Fy
LVYKA = 0;% KAPPA INDUCED PLYSTEER
LS = 0;   % MOMENT ARM OF Mz 

%* OTHER
LCZ = 1; % RADIAL TIRE STIFFNESS
LMX = 0; % OVERTURNING COUPLE STIFFNESS
LMY = 1; % ROLLING RESISTANCE MOMENT

%% NON-DIMENSIONAL PARAMETERS P Q S R 
%* P FOR FX
PCX1 = 1.6411;  
PCX2 = 1;
PDX1 = 1.1739;
PDX2 = -0.16395;
PEX1 = 0.46403;
PEX2 = 0.25022;
PEX3 = 0.067842;
PEX4 = -3.7604*10^(-5);
PKX1 = 22.303;
PKX2 = 0.48896;
PKX3 = 0.21253;
PHX1 = 0.0012297;
PHX2 = 0.0004318;
PVX1 = -8.8098*10^(-6);
PVX2 = 1.862*10^(-5);
%* P FOR FY
PCY1 = 1.3507;
PDY1 = 1.0489;
PDY2 = -0.18033;
PDY3 = -2.8821;
PEY1 = -0.0074722;
PEY2 = -0.0063208;
PEY3 = -9.9935;
PEY4 = -760.14;
PKY1 = -21.92;
PKY2 = 2.0012;
PKY3 = -0.024778;
PHY1 = 0.0026747;
PHY2 = 8.9094*10^(-5);
PHY3 = 0.031415;
PVY1 = 0.037318;
PVY2 = -0.010049;
PVY3 = -0.32931;
PVY4 = -0.69553;
%* Q FOR MZ
QHZ1 = 0.0047326;
QHZ2 = 0.0026687;
QHZ3 = 0.11998;
QHZ4 = 0.059083;
QBZ1 = 10.904;
QBZ2 = -1.8412;
QBZ3 = -0.52041;
QBZ4 = 0.039211;
QBZ5 = 0.41511;
QCZ1 = 1.2136;
QDZ1 = 0.093509;
QDZ2 = -0.0092183;
QDZ3 = -0.057061;
QDZ4 = 0.73954;
QEZ1 = -1.5697;
QEZ2 = 0.33394;
QEZ3 = 0;
QEZ4 = 0.26711;
QEZ5 = -3.594;
QBZ10 = 0;
QDZ6 = -0.0067783;
QDZ7 = 0.0052254;
QDZ8 = -0.18175;
QDZ9 = 0.029952;
%* Q for My rolling ressistance moment
QSY1 = 0.1;
QSY2 = 0;

%* COMBINED SLIP 
% R FOR FX
RBX1 = 13.276;
RBX2 = -13.778;
RCX1 = 1.2568;
REX1 = 0.65225;
REX2 = -0.24948;
RHX1 = 0.0050722;
% R FOR FY
RBY1 = 7.1433;
RBY2 = 9.1916;
RBY3 = -0.027856;
RCY1 = 1.0719;
REY1 = -0.27572;
REY2 = 0.32802;
RHY1 = 5.7448*10^(-6);
RHY2 = -3.1368*10^(-5);
RVY1 = -0.027825;
RVY2 = 0.053604;
RVY3 = -0.27568;
RVY4 = 12.12;
RVY5 = 1.9;
RVY6 = -10.704;
% S FOR MZ
SSZ1 = 0.033372;
SSZ2 = 0;
SSZ3 = 0.56742;
SSZ4 = -0.24116;

%* SCALING VERTICAL LOAD Fz0' CHANGE dfz
dfz = (FZ-LFZ0*FZ0)./(LFZ0*FZ0);
%% LONGITUDINAL FORCE (PURE)
% FX0 = DX*SIN(CX*ATAN(BX*KX-EX*(BX*KX-ATAN(BX*KX))))+SVX
SHX = (PHX1+PHX2*dfz)*LHX;
KX = KAPPA+SHX;
CX = PCX1*LCX;
MUX = (PDX1+PDX2*dfz)*LMUX/(1+LMUV*VS/V0);
DX = MUX*FZ*1;
EX = (PEX1+PEX2*dfz+PEX3*dfz^2)*(1-PEX4*sign(KAPPA))*LEX;
KXKA = FZ*(PKX1+PKX2*dfz)*exp(PKX3*dfz)*LKX;
BX = KXKA/(CX*DX+0.1);
SVX = FZ*(PVX1+PVX2*dfz)*LVX*LMUX*1;
FX0 = DX*sin(CX*atan(BX*KX-EX*(BX*KX-atan(BX*KX))))+SVX;

%% LATERAL FORCE (PURE)
% FY0 = DY*sin(CY*atan(BY*ALY-EY*(BY*ALY-atan(BY*ALY))))+SVY
SHY = (PHY1+PHY2*dfz)*LHY+PHY3*sin(GAMMA)*LGAY*1+1-1;
ALY = ALPHA*sign(VS)+SHY; 
CY = PCY1*LCY;
MUY = (PDY1+PDY2*dfz)*(1-PDY3*sin(GAMMA)^2)*LMUY/(1+LMUV*VS/V0);
DY = MUY*FZ*1;
EY = (PEY1+PEY2*dfz)*(1-(PEY3+PEY4*sin(GAMMA))*sign(ALY))*LEY;
KYAL0 = PKY1*LFZ0*FZ0*sin(2*atan(FZ/(PKY2*LFZ0*FZ0)))*LKY;
KYAL = KYAL0*(1-PKY3*sin(GAMMA)^2)*1;
BY = KYAL/(CY*DY+0.1);
SVY = FZ*((PVY1+PVY2*dfz)*LVY+(PVY3+PVY4*dfz)*sin(GAMMA)*LGAY)*LMUY*1;
FY0 = DY*sin(CY*atan(BY*ALY-EY*(BY*ALY-atan(BY*ALY))))+SVY;

%% ALIGNING TORQUE (PURE)
% MZ0 = MZP+MZR0;
SHT =  QHZ1+QHZ2*dfz+(QHZ3+QHZ4*dfz)*sin(GAMMA);
ALT =  ALPHA*sign(VS)+SHT;
BT = (QBZ1+QBZ2*dfz+QBZ3*dfz^2)*(1+QBZ4*sin(GAMMA)+QBZ5*abs(sin(GAMMA)))*LKY/LMUY;
CT = QCZ1;
DT0 = FZ*(R0/(LFZ0*FZ0))*(QDZ1+QDZ2*dfz)*LT*sign(VS);
DT = DT0*(1+QDZ3*sin(GAMMA)+QDZ4*sin(GAMMA)^2)*1;
ET = (QEZ1+QEZ2*dfz+QEZ3*dfz^2)*(1+(QEZ4+QEZ5*sin(GAMMA))*2/pi*atan(BT*CT*ALT));
T0 = DT*cos(CT*atan(BT*ALT-ET*(BT*ALT-atan(BT*ALT))))*(cos(ALPHA));
MZP = -T0*FY0;

SHF = SHY+SVY/(KYAL+0.1);
ALR = ALPHA*sign(VS)+SHF;
BR = QBZ10*BY*CY;
CR = 1;
DR = FZ*R0*((QDZ6+QDZ7*dfz)*LMR*1+(QDZ8+QDZ9*dfz)*sin(GAMMA)*LGAZ*1)*(cos(ALPHA))*LMUY*sign(VS)+1-1;
MZR0 = DR*cos(CR*atan(BR*ALR));

MZ0 = MZP+MZR0;

%% LONGITUDINAL FORCE COMBINED SLIP
SHXAL = RHX1;
EXAL = REX1+REX2*dfz;
CXAL = RCX1;
BXAL = RBX1*cos(atan(RBX2*KAPPA))*LXAL;
ALS = ALPHA*sign(VS)+SHXAL;
GXAL0 = cos(CXAL*atan(BXAL*SHXAL-EXAL*(BXAL*SHXAL-atan(BXAL*SHXAL))));
GXAL = cos(CXAL*atan(BXAL*ALS-EXAL*(BXAL*ALS-atan(BXAL*ALS))))/(GXAL0);
FX = GXAL*FX0;

%% LATERAL FORCE COMBINED SLIP
DVYK = MUY*FZ*(RVY1+RVY2*dfz+RVY3*sin(GAMMA))*cos(atan(RVY4*ALPHA*sign(VS)))*1;
SVYK = DVYK*sin(RVY5*atan(RVY6*KAPPA));
SHYK = RHY1+RHY2*dfz;
EYK = REY1+REY2*dfz;
CYK = RCY1;
BYK = RBY1*cos(atan(RBY2*(ALPHA*sign(VS)-RBY3)))*LYKA;
KS = KAPPA+SHYK;
GYK0 = cos(CYK*atan(BYK*SHYK-EYK*(BYK*SHYK-atan(BYK*SHYK))));
GYK = cos(CYK*atan(BYK*KS-EYK*(BYK*KS-atan(BYK*KS))))./(GYK0);
FY = GYK*FY0+SVYK;

%% ALIGNING TORQUE COMBINED SLIP
AREQ = sqrt(ALR^2+(KXKA/(KYAL+0.1))^2*KAPPA^2)*sign(ALR);
ATEQ = sqrt(ALT^2+(KXKA/(KYAL+0.1))^2*KAPPA^2)*sign(ALT);
S = R0*(SSZ1+SSZ2*(FY/(FZ0*LFZ0))+(SSZ3+SSZ4*dfz)*sin(GAMMA))*LS;
MZR = DR*cos(CR*atan(BR*AREQ));
FYP = FY-SVYK;
T = DT*cos(CT*atan(BT*ALT-ET*(BT*ATEQ-atan(BT*ATEQ))))*(cos(ALPHA));
MZP = -T*FYP;
MZ = MZP+MZR+S*FX;

%% ROLLING RESSISTANCE MOMENT MY
MY = -FZ*R0*(QSY1*atan(VS*(1-abs(KAPPA))/V0)+QSY2*FX/(LFZ0*FZ0))*LMY;

% y=[FX0,FY0,MZ0,MY]';

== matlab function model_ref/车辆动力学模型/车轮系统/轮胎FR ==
function [FX0,FY0,MZ0,MY]=MagicTire(FZ,KAPPA,ALPHA,VS)
% The Magic tire model fcn

% INPUT 1 : VERTICAL LOAD FORCE --- FZ
% INPUT 2 : TIRE SIDESLIP ANGLE --- ALPHA
% INPUT 3 : TIRE LONGITUDINAL SLIP RATIO --- KAPPA
% INPUT 4 : TIRE CONTACT CENTER VELOCITY --- VS
% INPUT 5 : TIRE CAMBER ---GAMMA
GAMMA=0;
ALPHA=-ALPHA;           % 根据侧倾角定义
%% TIRE DATA
R0 = 0.344; % TIRE RADIUS (M)
Re = 0.314;   % EFFECTIVE RADIUS (M)
V0 = 16.6;  % REFERENCE VELOCITY 60 (KM/H)
FZ0 = 4850; % UNLOAD NOMINAL FORCE (N)

%% SCALIING FACTORS LAMDA
%* PURE SLIP
LFZ0 = 1; % NOMINAL LOAD
LMUX = 1; % PEAK FRICTION COEFFICENT LONGITUDINAL
LMUY = 1; % PEAK FRICTION COEFFICENT LATERAL
LMUV = 1; % SLIP DECAYING FRICTION
LKX = 1;  % BRAKE SLIP STIFFNESS
LKY = 1;  % CORNERING STIFFNESS
LCX = 1;  % SHAPE FACTOR
LCY = 1;  % SHAPE FACTOR
LEX = 1;  % CURVATURE FACTOR
LEY = 1;  % CURVATURE FACTOR
LHX = 0;  % HORIZONTAL FACTOR
LHY = 0;  % HORIZONTAL FACTOR
LVX = 0;  % VERTICAL FACTOR
LVY = 0;  % 
LGAY = 1; % CAMBER FORCE STIFFNESS
LGAZ = 0; % CAMBER TORQUE STIFFNESS
LT = 1;   % PNEUMATIC TRAIL
LMR = 0;  % RESIDUAL TORQUE (LRES IN EXCEL)

%* COMBINED SLIP
LXAL = 0; % ALPHA INFLUENCE ON Fx
LYKA = 0; % KAPPA INFLUENCE ON Fy
LVYKA = 0;% KAPPA INDUCED PLYSTEER
LS = 0;   % MOMENT ARM OF Mz 

%* OTHER
LCZ = 1; % RADIAL TIRE STIFFNESS
LMX = 0; % OVERTURNING COUPLE STIFFNESS
LMY = 1; % ROLLING RESISTANCE MOMENT

%% NON-DIMENSIONAL PARAMETERS P Q S R 
%* P FOR FX
PCX1 = 1.6411;  
PCX2 = 1;
PDX1 = 1.1739;
PDX2 = -0.16395;
PEX1 = 0.46403;
PEX2 = 0.25022;
PEX3 = 0.067842;
PEX4 = -3.7604*10^(-5);
PKX1 = 22.303;
PKX2 = 0.48896;
PKX3 = 0.21253;
PHX1 = 0.0012297;
PHX2 = 0.0004318;
PVX1 = -8.8098*10^(-6);
PVX2 = 1.862*10^(-5);
%* P FOR FY
PCY1 = 1.3507;
PDY1 = 1.0489;
PDY2 = -0.18033;
PDY3 = -2.8821;
PEY1 = -0.0074722;
PEY2 = -0.0063208;
PEY3 = -9.9935;
PEY4 = -760.14;
PKY1 = -21.92;
PKY2 = 2.0012;
PKY3 = -0.024778;
PHY1 = 0.0026747;
PHY2 = 8.9094*10^(-5);
PHY3 = 0.031415;
PVY1 = 0.037318;
PVY2 = -0.010049;
PVY3 = -0.32931;
PVY4 = -0.69553;
%* Q FOR MZ
QHZ1 = 0.0047326;
QHZ2 = 0.0026687;
QHZ3 = 0.11998;
QHZ4 = 0.059083;
QBZ1 = 10.904;
QBZ2 = -1.8412;
QBZ3 = -0.52041;
QBZ4 = 0.039211;
QBZ5 = 0.41511;
QCZ1 = 1.2136;
QDZ1 = 0.093509;
QDZ2 = -0.0092183;
QDZ3 = -0.057061;
QDZ4 = 0.73954;
QEZ1 = -1.5697;
QEZ2 = 0.33394;
QEZ3 = 0;
QEZ4 = 0.26711;
QEZ5 = -3.594;
QBZ10 = 0;
QDZ6 = -0.0067783;
QDZ7 = 0.0052254;
QDZ8 = -0.18175;
QDZ9 = 0.029952;
%* Q for My rolling ressistance moment
QSY1 = 0.1;
QSY2 = 0;

%* COMBINED SLIP 
% R FOR FX
RBX1 = 13.276;
RBX2 = -13.778;
RCX1 = 1.2568;
REX1 = 0.65225;
REX2 = -0.24948;
RHX1 = 0.0050722;
% R FOR FY
RBY1 = 7.1433;
RBY2 = 9.1916;
RBY3 = -0.027856;
RCY1 = 1.0719;
REY1 = -0.27572;
REY2 = 0.32802;
RHY1 = 5.7448*10^(-6);
RHY2 = -3.1368*10^(-5);
RVY1 = -0.027825;
RVY2 = 0.053604;
RVY3 = -0.27568;
RVY4 = 12.12;
RVY5 = 1.9;
RVY6 = -10.704;
% S FOR MZ
SSZ1 = 0.033372;
SSZ2 = 0;
SSZ3 = 0.56742;
SSZ4 = -0.24116;

%* SCALING VERTICAL LOAD Fz0' CHANGE dfz
dfz = (FZ-LFZ0*FZ0)./(LFZ0*FZ0);
%% LONGITUDINAL FORCE (PURE)
% FX0 = DX*SIN(CX*ATAN(BX*KX-EX*(BX*KX-ATAN(BX*KX))))+SVX
SHX = (PHX1+PHX2*dfz)*LHX;
KX = KAPPA+SHX;
CX = PCX1*LCX;
MUX = (PDX1+PDX2*dfz)*LMUX/(1+LMUV*VS/V0);
DX = MUX*FZ*1;
EX = (PEX1+PEX2*dfz+PEX3*dfz^2)*(1-PEX4*sign(KAPPA))*LEX;
KXKA = FZ*(PKX1+PKX2*dfz)*exp(PKX3*dfz)*LKX;
BX = KXKA/(CX*DX+0.1);
SVX = FZ*(PVX1+PVX2*dfz)*LVX*LMUX*1;
FX0 = DX*sin(CX*atan(BX*KX-EX*(BX*KX-atan(BX*KX))))+SVX;

%% LATERAL FORCE (PURE)
% FY0 = DY*sin(CY*atan(BY*ALY-EY*(BY*ALY-atan(BY*ALY))))+SVY
SHY = (PHY1+PHY2*dfz)*LHY+PHY3*sin(GAMMA)*LGAY*1+1-1;
ALY = ALPHA*sign(VS)+SHY; 
CY = PCY1*LCY;
MUY = (PDY1+PDY2*dfz)*(1-PDY3*sin(GAMMA)^2)*LMUY/(1+LMUV*VS/V0);
DY = MUY*FZ*1;
EY = (PEY1+PEY2*dfz)*(1-(PEY3+PEY4*sin(GAMMA))*sign(ALY))*LEY;
KYAL0 = PKY1*LFZ0*FZ0*sin(2*atan(FZ/(PKY2*LFZ0*FZ0)))*LKY;
KYAL = KYAL0*(1-PKY3*sin(GAMMA)^2)*1;
BY = KYAL/(CY*DY+0.1);
SVY = FZ*((PVY1+PVY2*dfz)*LVY+(PVY3+PVY4*dfz)*sin(GAMMA)*LGAY)*LMUY*1;
FY0 = DY*sin(CY*atan(BY*ALY-EY*(BY*ALY-atan(BY*ALY))))+SVY;

%% ALIGNING TORQUE (PURE)
% MZ0 = MZP+MZR0;
SHT =  QHZ1+QHZ2*dfz+(QHZ3+QHZ4*dfz)*sin(GAMMA);
ALT =  ALPHA*sign(VS)+SHT;
BT = (QBZ1+QBZ2*dfz+QBZ3*dfz^2)*(1+QBZ4*sin(GAMMA)+QBZ5*abs(sin(GAMMA)))*LKY/LMUY;
CT = QCZ1;
DT0 = FZ*(R0/(LFZ0*FZ0))*(QDZ1+QDZ2*dfz)*LT*sign(VS);
DT = DT0*(1+QDZ3*sin(GAMMA)+QDZ4*sin(GAMMA)^2)*1;
ET = (QEZ1+QEZ2*dfz+QEZ3*dfz^2)*(1+(QEZ4+QEZ5*sin(GAMMA))*2/pi*atan(BT*CT*ALT));
T0 = DT*cos(CT*atan(BT*ALT-ET*(BT*ALT-atan(BT*ALT))))*(cos(ALPHA));
MZP = -T0*FY0;

SHF = SHY+SVY/(KYAL+0.1);
ALR = ALPHA*sign(VS)+SHF;
BR = QBZ10*BY*CY;
CR = 1;
DR = FZ*R0*((QDZ6+QDZ7*dfz)*LMR*1+(QDZ8+QDZ9*dfz)*sin(GAMMA)*LGAZ*1)*(cos(ALPHA))*LMUY*sign(VS)+1-1;
MZR0 = DR*cos(CR*atan(BR*ALR));

MZ0 = MZP+MZR0;

%% LONGITUDINAL FORCE COMBINED SLIP
SHXAL = RHX1;
EXAL = REX1+REX2*dfz;
CXAL = RCX1;
BXAL = RBX1*cos(atan(RBX2*KAPPA))*LXAL;
ALS = ALPHA*sign(VS)+SHXAL;
GXAL0 = cos(CXAL*atan(BXAL*SHXAL-EXAL*(BXAL*SHXAL-atan(BXAL*SHXAL))));
GXAL = cos(CXAL*atan(BXAL*ALS-EXAL*(BXAL*ALS-atan(BXAL*ALS))))/(GXAL0);
FX = GXAL*FX0;

%% LATERAL FORCE COMBINED SLIP
DVYK = MUY*FZ*(RVY1+RVY2*dfz+RVY3*sin(GAMMA))*cos(atan(RVY4*ALPHA*sign(VS)))*1;
SVYK = DVYK*sin(RVY5*atan(RVY6*KAPPA));
SHYK = RHY1+RHY2*dfz;
EYK = REY1+REY2*dfz;
CYK = RCY1;
BYK = RBY1*cos(atan(RBY2*(ALPHA*sign(VS)-RBY3)))*LYKA;
KS = KAPPA+SHYK;
GYK0 = cos(CYK*atan(BYK*SHYK-EYK*(BYK*SHYK-atan(BYK*SHYK))));
GYK = cos(CYK*atan(BYK*KS-EYK*(BYK*KS-atan(BYK*KS))))./(GYK0);
FY = GYK*FY0+SVYK;

%% ALIGNING TORQUE COMBINED SLIP
AREQ = sqrt(ALR^2+(KXKA/(KYAL+0.1))^2*KAPPA^2)*sign(ALR);
ATEQ = sqrt(ALT^2+(KXKA/(KYAL+0.1))^2*KAPPA^2)*sign(ALT);
S = R0*(SSZ1+SSZ2*(FY/(FZ0*LFZ0))+(SSZ3+SSZ4*dfz)*sin(GAMMA))*LS;
MZR = DR*cos(CR*atan(BR*AREQ));
FYP = FY-SVYK;
T = DT*cos(CT*atan(BT*ALT-ET*(BT*ATEQ-atan(BT*ATEQ))))*(cos(ALPHA));
MZP = -T*FYP;
MZ = MZP+MZR+S*FX;

%% ROLLING RESSISTANCE MOMENT MY
MY = -FZ*R0*(QSY1*atan(VS*(1-abs(KAPPA))/V0)+QSY2*FX/(LFZ0*FZ0))*LMY;

% y=[FX0,FY0,MZ0,MY]';

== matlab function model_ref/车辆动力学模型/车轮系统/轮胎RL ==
function [FX0,FY0,MZ0,MY]=MagicTire(FZ,KAPPA,ALPHA,VS)
% The Magic tire model fcn

% INPUT 1 : VERTICAL LOAD FORCE --- FZ
% INPUT 2 : TIRE SIDESLIP ANGLE --- ALPHA
% INPUT 3 : TIRE LONGITUDINAL SLIP RATIO --- KAPPA
% INPUT 4 : TIRE CONTACT CENTER VELOCITY --- VS
% INPUT 5 : TIRE CAMBER ---GAMMA
GAMMA=0;
ALPHA=-ALPHA;           % 根据侧倾角定义
%% TIRE DATA
R0 = 0.344; % TIRE RADIUS (M)
Re = 0.314;   % EFFECTIVE RADIUS (M)
V0 = 16.6;  % REFERENCE VELOCITY 60 (KM/H)
FZ0 = 4850; % UNLOAD NOMINAL FORCE (N)

%% SCALIING FACTORS LAMDA
%* PURE SLIP
LFZ0 = 1; % NOMINAL LOAD
LMUX = 1; % PEAK FRICTION COEFFICENT LONGITUDINAL
LMUY = 1; % PEAK FRICTION COEFFICENT LATERAL
LMUV = 1; % SLIP DECAYING FRICTION
LKX = 1;  % BRAKE SLIP STIFFNESS
LKY = 1;  % CORNERING STIFFNESS
LCX = 1;  % SHAPE FACTOR
LCY = 1;  % SHAPE FACTOR
LEX = 1;  % CURVATURE FACTOR
LEY = 1;  % CURVATURE FACTOR
LHX = 0;  % HORIZONTAL FACTOR
LHY = 0;  % HORIZONTAL FACTOR
LVX = 0;  % VERTICAL FACTOR
LVY = 0;  % 
LGAY = 1; % CAMBER FORCE STIFFNESS
LGAZ = 0; % CAMBER TORQUE STIFFNESS
LT = 1;   % PNEUMATIC TRAIL
LMR = 0;  % RESIDUAL TORQUE (LRES IN EXCEL)

%* COMBINED SLIP
LXAL = 0; % ALPHA INFLUENCE ON Fx
LYKA = 0; % KAPPA INFLUENCE ON Fy
LVYKA = 0;% KAPPA INDUCED PLYSTEER
LS = 0;   % MOMENT ARM OF Mz 

%* OTHER
LCZ = 1; % RADIAL TIRE STIFFNESS
LMX = 0; % OVERTURNING COUPLE STIFFNESS
LMY = 1; % ROLLING RESISTANCE MOMENT

%% NON-DIMENSIONAL PARAMETERS P Q S R 
%* P FOR FX
PCX1 = 1.6411;  
PCX2 = 1;
PDX1 = 1.1739;
PDX2 = -0.16395;
PEX1 = 0.46403;
PEX2 = 0.25022;
PEX3 = 0.067842;
PEX4 = -3.7604*10^(-5);
PKX1 = 22.303;
PKX2 = 0.48896;
PKX3 = 0.21253;
PHX1 = 0.0012297;
PHX2 = 0.0004318;
PVX1 = -8.8098*10^(-6);
PVX2 = 1.862*10^(-5);
%* P FOR FY
PCY1 = 1.3507;
PDY1 = 1.0489;
PDY2 = -0.18033;
PDY3 = -2.8821;
PEY1 = -0.0074722;
PEY2 = -0.0063208;
PEY3 = -9.9935;
PEY4 = -760.14;
PKY1 = -21.92;
PKY2 = 2.0012;
PKY3 = -0.024778;
PHY1 = 0.0026747;
PHY2 = 8.9094*10^(-5);
PHY3 = 0.031415;
PVY1 = 0.037318;
PVY2 = -0.010049;
PVY3 = -0.32931;
PVY4 = -0.69553;
%* Q FOR MZ
QHZ1 = 0.0047326;
QHZ2 = 0.0026687;
QHZ3 = 0.11998;
QHZ4 = 0.059083;
QBZ1 = 10.904;
QBZ2 = -1.8412;
QBZ3 = -0.52041;
QBZ4 = 0.039211;
QBZ5 = 0.41511;
QCZ1 = 1.2136;
QDZ1 = 0.093509;
QDZ2 = -0.0092183;
QDZ3 = -0.057061;
QDZ4 = 0.73954;
QEZ1 = -1.5697;
QEZ2 = 0.33394;
QEZ3 = 0;
QEZ4 = 0.26711;
QEZ5 = -3.594;
QBZ10 = 0;
QDZ6 = -0.0067783;
QDZ7 = 0.0052254;
QDZ8 = -0.18175;
QDZ9 = 0.029952;
%* Q for My rolling ressistance moment
QSY1 = 0.1;
QSY2 = 0;

%* COMBINED SLIP 
% R FOR FX
RBX1 = 13.276;
RBX2 = -13.778;
RCX1 = 1.2568;
REX1 = 0.65225;
REX2 = -0.24948;
RHX1 = 0.0050722;
% R FOR FY
RBY1 = 7.1433;
RBY2 = 9.1916;
RBY3 = -0.027856;
RCY1 = 1.0719;
REY1 = -0.27572;
REY2 = 0.32802;
RHY1 = 5.7448*10^(-6);
RHY2 = -3.1368*10^(-5);
RVY1 = -0.027825;
RVY2 = 0.053604;
RVY3 = -0.27568;
RVY4 = 12.12;
RVY5 = 1.9;
RVY6 = -10.704;
% S FOR MZ
SSZ1 = 0.033372;
SSZ2 = 0;
SSZ3 = 0.56742;
SSZ4 = -0.24116;

%* SCALING VERTICAL LOAD Fz0' CHANGE dfz
dfz = (FZ-LFZ0*FZ0)./(LFZ0*FZ0);
%% LONGITUDINAL FORCE (PURE)
% FX0 = DX*SIN(CX*ATAN(BX*KX-EX*(BX*KX-ATAN(BX*KX))))+SVX
SHX = (PHX1+PHX2*dfz)*LHX;
KX = KAPPA+SHX;
CX = PCX1*LCX;
MUX = (PDX1+PDX2*dfz)*LMUX/(1+LMUV*VS/V0);
DX = MUX*FZ*1;
EX = (PEX1+PEX2*dfz+PEX3*dfz^2)*(1-PEX4*sign(KAPPA))*LEX;
KXKA = FZ*(PKX1+PKX2*dfz)*exp(PKX3*dfz)*LKX;
BX = KXKA/(CX*DX+0.1);
SVX = FZ*(PVX1+PVX2*dfz)*LVX*LMUX*1;
FX0 = DX*sin(CX*atan(BX*KX-EX*(BX*KX-atan(BX*KX))))+SVX;

%% LATERAL FORCE (PURE)
% FY0 = DY*sin(CY*atan(BY*ALY-EY*(BY*ALY-atan(BY*ALY))))+SVY
SHY = (PHY1+PHY2*dfz)*LHY+PHY3*sin(GAMMA)*LGAY*1+1-1;
ALY = ALPHA*sign(VS)+SHY; 
CY = PCY1*LCY;
MUY = (PDY1+PDY2*dfz)*(1-PDY3*sin(GAMMA)^2)*LMUY/(1+LMUV*VS/V0);
DY = MUY*FZ*1;
EY = (PEY1+PEY2*dfz)*(1-(PEY3+PEY4*sin(GAMMA))*sign(ALY))*LEY;
KYAL0 = PKY1*LFZ0*FZ0*sin(2*atan(FZ/(PKY2*LFZ0*FZ0)))*LKY;
KYAL = KYAL0*(1-PKY3*sin(GAMMA)^2)*1;
BY = KYAL/(CY*DY+0.1);
SVY = FZ*((PVY1+PVY2*dfz)*LVY+(PVY3+PVY4*dfz)*sin(GAMMA)*LGAY)*LMUY*1;
FY0 = DY*sin(CY*atan(BY*ALY-EY*(BY*ALY-atan(BY*ALY))))+SVY;

%% ALIGNING TORQUE (PURE)
% MZ0 = MZP+MZR0;
SHT =  QHZ1+QHZ2*dfz+(QHZ3+QHZ4*dfz)*sin(GAMMA);
ALT =  ALPHA*sign(VS)+SHT;
BT = (QBZ1+QBZ2*dfz+QBZ3*dfz^2)*(1+QBZ4*sin(GAMMA)+QBZ5*abs(sin(GAMMA)))*LKY/LMUY;
CT = QCZ1;
DT0 = FZ*(R0/(LFZ0*FZ0))*(QDZ1+QDZ2*dfz)*LT*sign(VS);
DT = DT0*(1+QDZ3*sin(GAMMA)+QDZ4*sin(GAMMA)^2)*1;
ET = (QEZ1+QEZ2*dfz+QEZ3*dfz^2)*(1+(QEZ4+QEZ5*sin(GAMMA))*2/pi*atan(BT*CT*ALT));
T0 = DT*cos(CT*atan(BT*ALT-ET*(BT*ALT-atan(BT*ALT))))*(cos(ALPHA));
MZP = -T0*FY0;

SHF = SHY+SVY/(KYAL+0.1);
ALR = ALPHA*sign(VS)+SHF;
BR = QBZ10*BY*CY;
CR = 1;
DR = FZ*R0*((QDZ6+QDZ7*dfz)*LMR*1+(QDZ8+QDZ9*dfz)*sin(GAMMA)*LGAZ*1)*(cos(ALPHA))*LMUY*sign(VS)+1-1;
MZR0 = DR*cos(CR*atan(BR*ALR));

MZ0 = MZP+MZR0;

%% LONGITUDINAL FORCE COMBINED SLIP
SHXAL = RHX1;
EXAL = REX1+REX2*dfz;
CXAL = RCX1;
BXAL = RBX1*cos(atan(RBX2*KAPPA))*LXAL;
ALS = ALPHA*sign(VS)+SHXAL;
GXAL0 = cos(CXAL*atan(BXAL*SHXAL-EXAL*(BXAL*SHXAL-atan(BXAL*SHXAL))));
GXAL = cos(CXAL*atan(BXAL*ALS-EXAL*(BXAL*ALS-atan(BXAL*ALS))))/(GXAL0);
FX = GXAL*FX0;

%% LATERAL FORCE COMBINED SLIP
DVYK = MUY*FZ*(RVY1+RVY2*dfz+RVY3*sin(GAMMA))*cos(atan(RVY4*ALPHA*sign(VS)))*1;
SVYK = DVYK*sin(RVY5*atan(RVY6*KAPPA));
SHYK = RHY1+RHY2*dfz;
EYK = REY1+REY2*dfz;
CYK = RCY1;
BYK = RBY1*cos(atan(RBY2*(ALPHA*sign(VS)-RBY3)))*LYKA;
KS = KAPPA+SHYK;
GYK0 = cos(CYK*atan(BYK*SHYK-EYK*(BYK*SHYK-atan(BYK*SHYK))));
GYK = cos(CYK*atan(BYK*KS-EYK*(BYK*KS-atan(BYK*KS))))./(GYK0);
FY = GYK*FY0+SVYK;

%% ALIGNING TORQUE COMBINED SLIP
AREQ = sqrt(ALR^2+(KXKA/(KYAL+0.1))^2*KAPPA^2)*sign(ALR);
ATEQ = sqrt(ALT^2+(KXKA/(KYAL+0.1))^2*KAPPA^2)*sign(ALT);
S = R0*(SSZ1+SSZ2*(FY/(FZ0*LFZ0))+(SSZ3+SSZ4*dfz)*sin(GAMMA))*LS;
MZR = DR*cos(CR*atan(BR*AREQ));
FYP = FY-SVYK;
T = DT*cos(CT*atan(BT*ALT-ET*(BT*ATEQ-atan(BT*ATEQ))))*(cos(ALPHA));
MZP = -T*FYP;
MZ = MZP+MZR+S*FX;

%% ROLLING RESSISTANCE MOMENT MY
MY = -FZ*R0*(QSY1*atan(VS*(1-abs(KAPPA))/V0)+QSY2*FX/(LFZ0*FZ0))*LMY;

% y=[FX0,FY0,MZ0,MY]';
